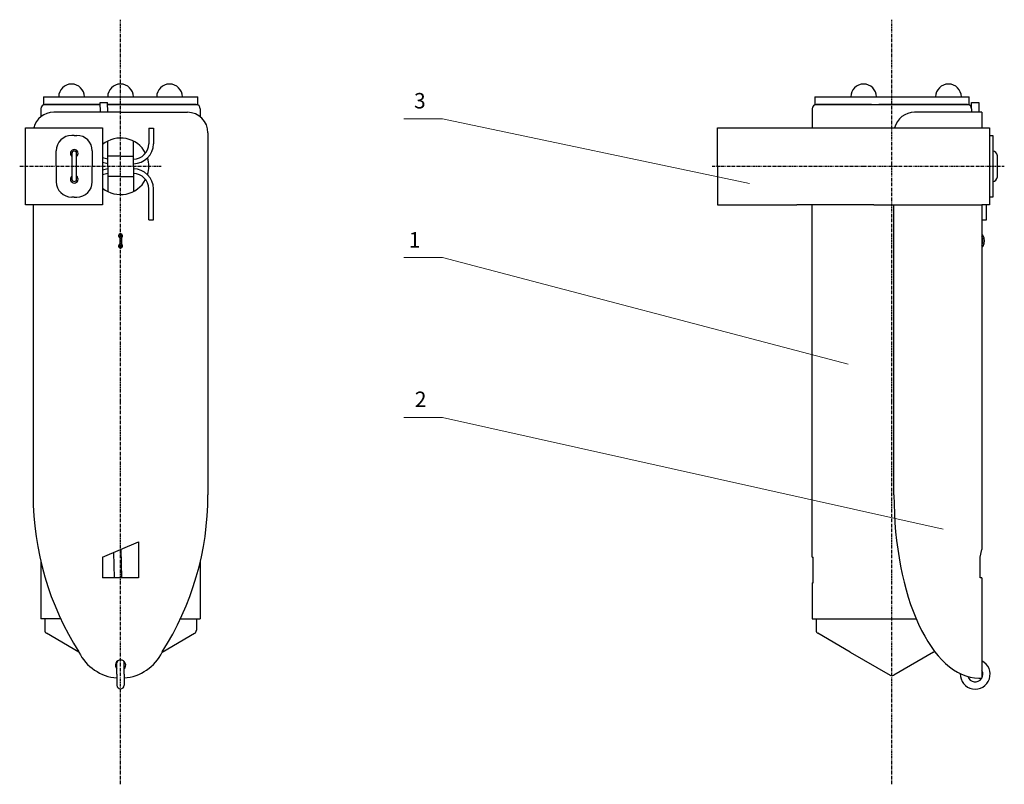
# Model space of a CAD drawing. Units: millimetres. Extents: x -20 to 172, y 40 to 189.
import ezdxf

# ---------------------------------------------------------------- set-up
doc = ezdxf.new("R2010")
doc.units = ezdxf.units.MM
doc.header["$LTSCALE"] = 0.2
doc.linetypes.add('ACAD_ISO10W100', pattern=[18, 12, -3, 0, -3])

msp = doc.modelspace()

# ---------------------------------------------------------------- linework, layer by layer
at = {"color": 1, "linetype": 'ACAD_ISO10W100', "lineweight": 25, "ltscale": 0.25}
for p, q in [((0, 114.83), (0, 189.15)), ((150, 114.83), (150, 189.15)), ((-19.62, 160.65), (7.88, 160.65)), ((115.05, 160.65), (116.87, 160.65)), ((116.87, 160.65), (144.36, 160.65)), ((144.36, 160.65), (171.86, 160.65)), ((0, 40.5), (0, 114.83)), ((150, 40.5), (150, 114.83))]:
    msp.add_line(p, q, dxfattribs=at)
at = {"color": 7, "lineweight": 30, "ltscale": 0.25}
for p, q in [((-15, 174.15), (15, 174.15)), ((-15, 174.15), (-15, 172.65)), ((-15, 172.65), (-3.94, 172.65)), ((-3.94, 172.65), (-14.7, 172.65)), ((-3.9, 171.15), (-3.96, 173.05)), ((-3.96, 173.05), (-2.56, 173.05)), ((-2.5, 171.15), (-2.56, 173.05)), ((-2.5, 172.65), (-2.54, 172.65)), ((14.7, 172.65), (-2.5, 172.65)), ((-2.5, 172.65), (15, 172.65)), ((15, 172.65), (15, 174.15)), ((135, 174.15), (165, 174.15)), ((135, 174.15), (135, 172.65)), ((135, 172.65), (146.06, 172.65)), ((146.06, 172.65), (135.3, 172.65)), ((146.06, 172.65), (147.46, 172.65)), ((147.5, 172.65), (147.46, 172.65)), ((147.5, 172.65), (165, 172.65)), ((164.7, 172.65), (147.5, 172.65)), ((165, 172.65), (165, 174.15)), ((165.5, 173.05), (166.9, 173.05)), ((165.5, 171.85), (165.5, 173.05)), ((166.9, 173.05), (166.9, 171.15)), ((-15.5, 171.85), (-15.5, 170.27)), ((0, 171.15), (-13, 171.15)), ((0, 171.15), (13, 171.15)), ((15.5, 171.85), (15.5, 170.27)), ((134.5, 171.85), (134.5, 168.15)), ((167.5, 171.15), (154.4, 171.15)), ((165.5, 171.85), (165.5, 171.15)), ((167.5, 171.15), (167.5, 168.15)), ((-18.5, 153.15), (-18.5, 168.15)), ((-18.5, 168.15), (-3.5, 168.15)), ((-9, 166.65), (-9.5, 166.65)), ((-9, 166.65), (-8.5, 166.65)), ((-3.5, 168.15), (-3.5, 153.15)), ((5.5, 168.05), (6.4, 168.05)), ((5.5, 168.05), (5.5, 165.05)), ((6.4, 168.05), (6.4, 165.05)), ((17, 167.15), (17, 96.76)), ((116.1, 160.65), (116.1, 168.15)), ((116.1, 168.15), (131.5, 168.15)), ((131.5, 168.15), (146.5, 168.15)), ((146.5, 168.15), (167.5, 168.15)), ((167.5, 168.15), (169, 168.15)), ((169, 168.15), (169, 153.15)), ((169, 166.65), (169.6, 166.65)), ((169.6, 166.65), (169.6, 154.65)), ((-2.5, 160.65), (-2.5, 165.55)), ((2.5, 160.65), (2.5, 165.55)), ((-12.5, 160.65), (-12.5, 163.65)), ((-9.45, 163.15), (-9.45, 158.15)), ((-8.31, 163.45), (-8.89, 163.59)), ((-8.55, 158.15), (-8.55, 163.15)), ((-5.5, 163.65), (-5.5, 160.65)), ((-8.52, 162.58), (-8.55, 162.58)), ((-2.5, 162.05), (-3.5, 162.29)), ((-2.5, 161.15), (-3.5, 161.39)), ((0, 162.65), (-2.5, 162.65)), ((0, 162.65), (2.5, 162.65)), ((170.5, 158.6), (170.5, 162.7)), ((-12.5, 160.65), (-12.5, 157.65)), ((-5.5, 157.65), (-5.5, 160.65)), ((-2.5, 160.15), (-3.5, 159.92)), ((-2.5, 159.25), (-3.5, 159.01)), ((-2.5, 160.65), (-2.5, 155.75)), ((2.5, 160.65), (2.5, 155.75)), ((116.1, 160.65), (116.1, 153.15)), ((-8.31, 157.85), (-8.89, 157.71)), ((-8.52, 158.73), (-8.55, 158.72)), ((0, 158.65), (-2.5, 158.65)), ((0, 158.65), (2.5, 158.65)), ((5.5, 150.25), (5.5, 156.25)), ((6.4, 150.25), (6.4, 156.25)), ((-9, 154.65), (-9.5, 154.65)), ((-9, 154.65), (-8.5, 154.65)), ((169.6, 154.65), (169, 154.65)), ((-3.5, 153.15), (-18.5, 153.15)), ((-17, 153.15), (-17, 96.76)), ((116.1, 153.15), (131.5, 153.15)), ((146.5, 153.15), (131.5, 153.15)), ((134.5, 84.65), (134.5, 153.15)), ((146.5, 153.15), (167.5, 153.15)), ((150.4, 96.78), (150.4, 153.15)), ((169, 153.15), (167.5, 153.15)), ((167.5, 153.15), (167.5, 86.15)), ((168.4, 150.25), (168.4, 153.15)), ((5.5, 150.25), (6.4, 150.25)), ((167.5, 150.25), (168.4, 150.25)), ((-0.15, 147.15), (-0.15, 145.15)), ((0.15, 147.15), (0.15, 145.15)), ((-3.5, 84.65), (3.5, 87.65)), ((0.04, 86.17), (0.21, 80.65)), ((3.5, 87.65), (3.5, 80.65)), ((-3.5, 84.65), (-3.5, 80.65)), ((-1.19, 80.65), (-1.34, 85.58)), ((134.5, 84.65), (134.7, 84.65)), ((134.7, 79.65), (134.7, 84.65)), ((167.14, 84.65), (167.5, 86.15)), ((167.14, 80.65), (167.14, 84.65)), ((-15.5, 83.79), (-15.5, 72.65)), ((15.5, 83.79), (15.5, 72.65)), ((3.5, 80.65), (-3.5, 80.65)), ((167.5, 80.65), (167.14, 80.65)), ((167.5, 80.65), (167.5, 61.15)), ((134.5, 79.65), (134.7, 79.65)), ((134.5, 79.65), (134.5, 72.65)), ((-11.63, 72.65), (-15.5, 72.65)), ((-14.75, 72.65), (-14.75, 70.46)), ((11.63, 72.65), (15.5, 72.65)), ((14.75, 72.65), (14.75, 70.46)), ((134.5, 72.65), (154.73, 72.65)), ((135.25, 72.65), (135.25, 70.46)), ((-8.09, 66.22), (-14.4, 69.86)), ((8.09, 66.22), (14.4, 69.86)), ((141.91, 66.22), (135.6, 69.86)), ((141.91, 66.22), (149.65, 61.75)), ((158.09, 66.22), (150.35, 61.75)), ((158.09, 66.22), (158.31, 66.34)), ((-0.7, 61.9), (-0.7, 64.11)), ((0.7, 61.9), (0.7, 64.1)), ((-0.7, 61.9), (-0.7, 59.75)), ((0.7, 61.9), (0.7, 59.75)), ((166.9, 61.15), (167.5, 61.15))]:
    msp.add_line(p, q, dxfattribs=at)
at = {"color": 7, "lineweight": 15, "ltscale": 0.25}
for p, q in [((55.06, 169.9), (62.6, 169.9)), ((122.33, 157.31), (62.6, 169.9)), ((62.6, 142.89), (55.06, 142.89)), ((141.52, 122.16), (62.6, 142.89)), ((62.6, 111.79), (55.06, 111.79)), ((159.97, 90.13), (62.6, 111.79))]:
    msp.add_line(p, q, dxfattribs=at)
at = {"color": 7, "lineweight": 30, "ltscale": 0.25}
for centre, radius, start, end in [((-9.53, 174.15), 2.5, 0, 180), ((0, 174.15), 2.5, 0, 180), ((9.53, 174.15), 2.5, 0, 180), ((144.5, 174.15), 2.5, 0, 180), ((161, 174.15), 2.5, 0, 180), ((-14.7, 171.85), 0.8, 90, 180), ((14.7, 171.85), 0.8, 0, 90), ((135.3, 171.85), 0.8, 90, 180), ((164.7, 171.85), 0.8, 0, 90), ((-13, 167.15), 4, 90, 165.5225), ((13, 167.15), 4, 0, 90), ((154.4, 167.15), 4, 90, 165.5225), ((-9.5, 163.65), 3, 90, 180), ((-8.5, 163.65), 3, 0, 90), ((0, 160.65), 5.5, 27.7254, 129.5212), ((2.5, 165.05), 3, 270, 0), ((2.5, 165.05), 3.9, 270, 0), ((-9, 163.15), 0.75, 306.8699, 233.1301), ((-9, 163.15), 0.45, 0, 180), ((169.6, 162.7), 0.9, 0, 90), ((0, 160.65), 5.5, 342.6983, 17.3017), ((2.5, 156.25), 3.9, 0, 90), ((2.5, 156.25), 3, 0, 90), ((-9.5, 157.65), 3, 180, 270), ((-9, 158.15), 0.75, 126.8699, 53.1301), ((-9, 158.15), 0.45, 180, 0), ((-8.5, 157.65), 3, 270, 0), ((0, 160.65), 5.5, 230.4788, 332.2746), ((169.6, 158.6), 0.9, 270, 0), ((0, 147.15), 0.4, 292.0243, 247.9757), ((0, 145.15), 0.4, 112.0243, 67.9757), ((0, 147.15), 0.15, 0, 180), ((167.5, 147), 0.3, 30, 90), ((165.8, 146.15), 1.9, 333.4587, 26.5413), ((165.8, 146.15), 2.2, 332.9877, 27.0123), ((0, 145.15), 0.15, 180, 0), ((167.5, 145.3), 0.3, 270, 330), ((39.81, 96.76), 56.81, 180, 212.5162), ((-39.81, 96.76), 56.81, 327.4838, 0), ((-14.05, 70.46), 0.7, 180, 240), ((14.05, 70.46), 0.7, 300, 0), ((135.95, 70.46), 0.7, 180, 240), ((0, 70.15), 9, 205.928, 265.5392), ((0, 70.15), 9, 274.4608, 334.072), ((0, 63.65), 1, 314.427, 225.573), ((0, 64.1), 0.7, 150.7845, 180), ((0, 64.1), 0.7, 0, 29.2155), ((166.2, 61.9), 2.9, 177.882, 63.3881), ((150, 62.35), 0.7, 240.0001, 299.9999), ((166.2, 61.9), 1.5, 197.4351, 30), ((0, 59.75), 0.7, 180, 0)]:
    msp.add_arc(centre, radius, start, end, dxfattribs=at)
msp.add_ellipse((167, 96.76), major_axis=(-0.1, -35.6), ratio=0.466244, start_param=4.713084, end_param=6.283185, dxfattribs=at)

# ---------------------------------------------------------------- texts
at = {"color": 7, "lineweight": 15, "ltscale": 0.25}
for s, p in [('3', (57.06, 171.9)), ('1', (56.06, 144.86)), ('2', (57.22, 113.85))]:
    msp.add_text(s, height=3, dxfattribs=at).set_placement(p)

doc.saveas('drawing.dxf')
